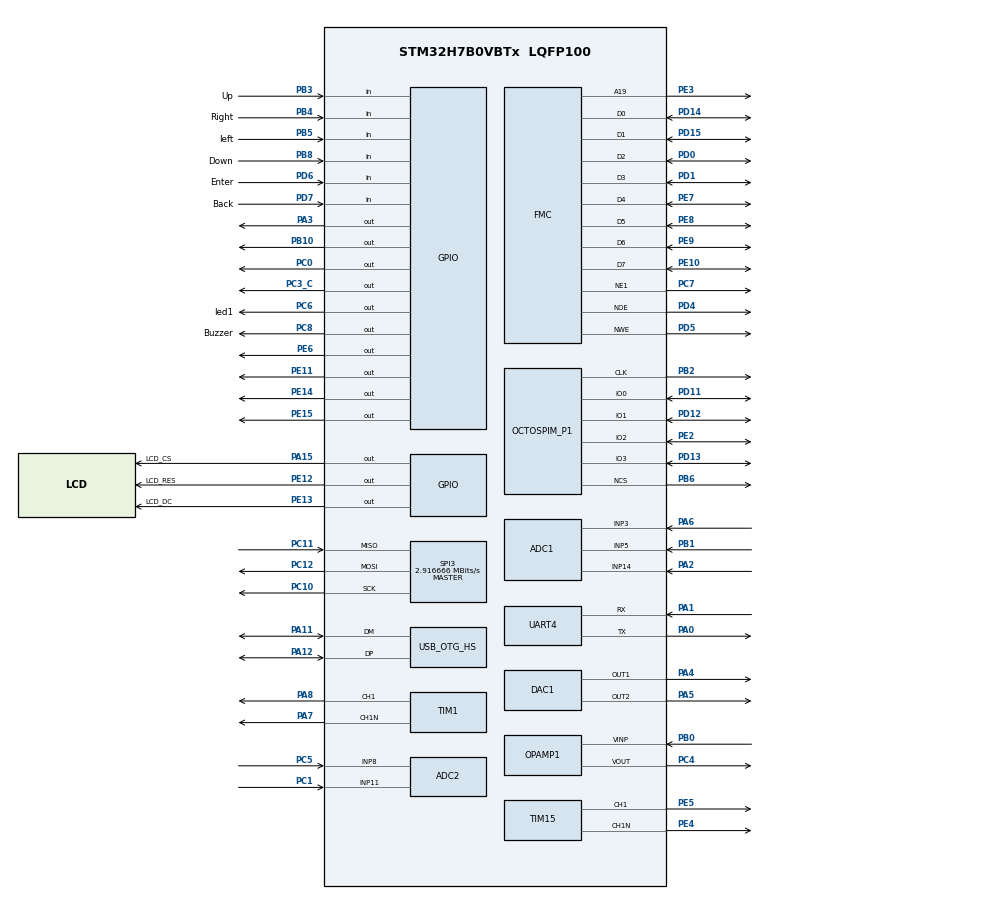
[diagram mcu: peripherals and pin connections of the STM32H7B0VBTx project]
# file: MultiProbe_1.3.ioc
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ADC1.Channel-0\#ChannelRegularConversion=ADC_CHANNEL_14
ADC1.ClockPrescaler=ADC_CLOCK_ASYNC_DIV2
ADC1.NbrOfConversionFlag=1
ADC1.OffsetNumber-0\#ChannelRegularConversion=ADC_OFFSET_NONE
ADC1.OffsetSignedSaturation-0\#ChannelRegularConversion=DISABLE
ADC1.Rank-0\#ChannelRegularConversion=1
ADC1.SamplingTime-0\#ChannelRegularConversion=ADC_SAMPLETIME_1CYCLE_5
ADC1.master=1
ADC2.Channel-0\#ChannelRegularConversion=ADC_CHANNEL_11
ADC2.ClockPrescaler=ADC_CLOCK_ASYNC_DIV2
ADC2.NbrOfConversionFlag=1
ADC2.OffsetNumber-0\#ChannelRegularConversion=ADC_OFFSET_NONE
ADC2.OffsetSignedSaturation-0\#ChannelRegularConversion=DISABLE
ADC2.Rank-0\#ChannelRegularConversion=1
ADC2.SamplingTime-0\#ChannelRegularConversion=ADC_SAMPLETIME_1CYCLE_5
DAC1.DAC_Channel-DAC_OUT1=DAC_CHANNEL_1
DAC1.DAC_Channel-DAC_OUT2=DAC_CHANNEL_2
Mcu.Family=STM32H7
Mcu.Name=STM32H7B0VBTx
Mcu.Package=LQFP100
NVIC.PriorityGroup=NVIC_PRIORITYGROUP_4
PA0.Mode=Asynchronous
PA0.Signal=UART4_TX
PA1.Mode=Asynchronous
PA1.Signal=UART4_RX
PA11.Mode=Device_Only_FS
PA11.Signal=USB_OTG_HS_DM
PA12.Mode=Device_Only_FS
PA12.Signal=USB_OTG_HS_DP
PA13.Mode=Serial_Wire
PA13.Signal=DEBUG_JTMS-SWDIO
PA14.Mode=Serial_Wire
PA14.Signal=DEBUG_JTCK-SWCLK
PA15.GPIO_Label=LCD_CS
PA15.PinState=GPIO_PIN_SET
PA15.Signal=GPIO_Output
PA2.Signal=ADCx_INP14
PA3.GPIO_PuPd=GPIO_PULLUP
PA3.PinState=GPIO_PIN_SET
PA3.Signal=GPIO_Output
PA4.Signal=COMP_DAC11_group
PA5.Signal=COMP_DAC12_group
PA6.Signal=ADCx_INP3
PA7.Mode=PWM Generation1 CH1 CH1N
PA7.Signal=TIM1_CH1N
PA8.Signal=S_TIM1_CH1
PB0.Mode=Follower
PB0.Signal=OPAMP1_VINP
PB1.Signal=ADCx_INP5
PB10.GPIO_PuPd=GPIO_PULLUP
PB10.PinState=GPIO_PIN_SET
PB10.Signal=GPIO_Output
PB12.Signal=SPI2_NSS
PB13.Signal=SPI2_SCK
PB2.Mode=O1_P1_CLK
PB2.Signal=OCTOSPIM_P1_CLK
PB3.GPIO_Label=Up
PB3.GPIO_PuPd=GPIO_PULLUP
PB3.Signal=GPIO_Input
PB4.GPIO_Label=Right
PB4.GPIO_PuPd=GPIO_PULLUP
PB4.Signal=GPIO_Input
PB5.GPIO_Label=left
PB5.GPIO_PuPd=GPIO_PULLUP
PB5.Signal=GPIO_Input
PB6.Mode=OCTOSPI1_Port1_NCS
PB6.Signal=OCTOSPIM_P1_NCS
PB8.GPIO_Label=Down
PB8.GPIO_PuPd=GPIO_PULLUP
PB8.Signal=GPIO_Input
PC0.GPIO_PuPd=GPIO_PULLUP
PC0.PinState=GPIO_PIN_SET
PC0.Signal=GPIO_Output
PC1.Signal=ADCx_INP11
PC10.Mode=Full_Duplex_Master
PC10.Signal=SPI3_SCK
PC11.Mode=Full_Duplex_Master
PC11.Signal=SPI3_MISO
PC12.Mode=Full_Duplex_Master
PC12.Signal=SPI3_MOSI
PC2_C.Signal=SPI2_MISO
PC3_C.GPIO_PuPd=GPIO_PULLUP
PC3_C.PinState=GPIO_PIN_SET
PC3_C.Signal=GPIO_Output
PC4.Mode=Follower
PC4.Signal=OPAMP1_VOUT
PC5.Signal=ADCx_INP8
PC6.GPIO_Label=led1
PC6.Signal=GPIO_Output
PC7.Mode=NorPsramChipSelect1_1
PC7.Signal=FMC_NE1
PC8.GPIO_Label=Buzzer
PC8.Signal=GPIO_Output
PD0.Signal=FMC_D2_DA2
PD1.Signal=FMC_D3_DA3
PD11.Mode=OCTOSPI1_IOL_Port1L
PD11.Signal=OCTOSPIM_P1_IO0
PD12.Mode=OCTOSPI1_IOL_Port1L
PD12.Signal=OCTOSPIM_P1_IO1
PD13.Mode=OCTOSPI1_IOL_Port1L
PD13.Signal=OCTOSPIM_P1_IO3
PD14.Signal=FMC_D0_DA0
PD15.Signal=FMC_D1_DA1
PD4.Signal=FMC_NOE
PD5.Signal=FMC_NWE
PD6.GPIO_Label=Enter
PD6.GPIO_PuPd=GPIO_PULLUP
PD6.Signal=GPIO_Input
PD7.GPIO_Label=Back
PD7.GPIO_PuPd=GPIO_PULLUP
PD7.Signal=GPIO_Input
PE10.Signal=FMC_D7_DA7
PE11.GPIO_PuPd=GPIO_PULLUP
PE11.PinState=GPIO_PIN_SET
PE11.Signal=GPIO_Output
PE12.GPIO_Label=LCD_RES
PE12.Signal=GPIO_Output
PE13.GPIO_Label=LCD_DC
PE13.Signal=GPIO_Output
PE14.GPIO_PuPd=GPIO_PULLUP
PE14.PinState=GPIO_PIN_SET
PE14.Signal=GPIO_Output
PE15.GPIO_PuPd=GPIO_PULLUP
PE15.PinState=GPIO_PIN_SET
PE15.Signal=GPIO_Output
PE2.Mode=OCTOSPI1_IOL_Port1L
PE2.Signal=OCTOSPIM_P1_IO2
PE3.Signal=FMC_A19
PE4.Mode=PWM Generation1 CH1 CH1N
PE4.Signal=TIM15_CH1N
PE5.Signal=S_TIM15_CH1
PE6.GPIO_ModeDefaultOutputPP=GPIO_MODE_OUTPUT_PP
PE6.GPIO_PuPd=GPIO_PULLUP
PE6.GPIO_Speed=GPIO_SPEED_FREQ_LOW
PE6.PinState=GPIO_PIN_SET
PE6.Signal=GPIO_Output
PE7.Signal=FMC_D4_DA4
PE8.Signal=FMC_D5_DA5
PE9.Signal=FMC_D6_DA6
PH0-OSC_IN.Mode=HSE-External-Oscillator
PH0-OSC_IN.Signal=RCC_OSC_IN
PH1-OSC_OUT.Mode=HSE-External-Oscillator
PH1-OSC_OUT.Signal=RCC_OSC_OUT
ProjectManager.HeapSize=0x200
ProjectManager.StackSize=0x400
ProjectManager.TargetToolchain=STM32CubeIDE
RCC.ADCFreq_Value=41666666.666666664
RCC.APB1Freq_Value=140000000
RCC.APB2Freq_Value=140000000
RCC.APB3Freq_Value=140000000
RCC.APB4Freq_Value=140000000
RCC.CDPPRE=RCC_APB3_DIV2
RCC.CDPPRE1=RCC_APB1_DIV2
RCC.CDPPRE2=RCC_APB2_DIV2
RCC.CortexFreq_Value=280000000
RCC.DIVM1=5
RCC.DIVM2=2
RCC.DIVN1=112
RCC.DIVN2=10
RCC.DIVP2=3
RCC.DIVQ1=12
RCC.HCLKFreq_Value=280000000
RCC.HSE_VALUE=25000000
RCC.PLL1_VCI_Range=RCC_PLL1VCIRANGE_3
RCC.PLL2FRACN=0
RCC.PLL2_VCI_Range=RCC_PLL2VCIRANGE_3
RCC.PLL3FRACN=0
RCC.PLLFRACN=0
RCC.SRDPPRE=RCC_APB4_DIV2
RCC.SYSCLKFreq_VALUE=280000000
RCC.SYSCLKSource=RCC_SYSCLKSOURCE_PLLCLK
RCC.USBFreq_Value=46666666.666666664
SH.ADCx_INP11.0=ADC2_INP11,IN11-Single-Ended
SH.ADCx_INP14.0=ADC1_INP14,IN14-Single-Ended
SH.ADCx_INP3.0=ADC1_INP3,IN3-Single-Ended
SH.ADCx_INP3.1=ADC2_INP3,IN3-Single-Ended
SH.ADCx_INP5.0=ADC1_INP5,IN5-Single-Ended
SH.ADCx_INP5.1=ADC2_INP5,IN5-Single-Ended
SH.ADCx_INP8.0=ADC2_INP8,IN8-Single-Ended
SH.COMP_DAC11_group.0=DAC1_OUT1,DAC_OUT1
SH.COMP_DAC12_group.0=DAC1_OUT2,DAC_OUT2
SH.FMC_A19.0=FMC_A19,A19_1
SH.FMC_D0_DA0.0=FMC_D0,8b-d1
SH.FMC_D1_DA1.0=FMC_D1,8b-d1
SH.FMC_D2_DA2.0=FMC_D2,8b-d1
SH.FMC_D3_DA3.0=FMC_D3,8b-d1
SH.FMC_D4_DA4.0=FMC_D4,8b-d1
SH.FMC_D5_DA5.0=FMC_D5,8b-d1
SH.FMC_D6_DA6.0=FMC_D6,8b-d1
SH.FMC_D7_DA7.0=FMC_D7,8b-d1
SH.FMC_NOE.0=FMC_NOE,Lcd1
SH.FMC_NWE.0=FMC_NWE,Lcd1
SH.S_TIM15_CH1.0=TIM15_CH1,PWM Generation1 CH1 CH1N
SH.S_TIM1_CH1.0=TIM1_CH1,PWM Generation1 CH1 CH1N
SPI3.BaudRatePrescaler=SPI_BAUDRATEPRESCALER_16
SPI3.CalculateBaudRate=2.916666 MBits/s
SPI3.DataSize=SPI_DATASIZE_8BIT
SPI3.Direction=SPI_DIRECTION_2LINES
SPI3.Mode=SPI_MODE_MASTER
SPI3.VirtualType=VM_MASTER
TIM1.Channel-PWM\ Generation1\ CH1\ CH1N=TIM_CHANNEL_1
TIM15.Channel-PWM\ Generation1\ CH1\ CH1N=TIM_CHANNEL_1
USB_OTG_HS.VirtualMode-Device_Only_FS=Device_Only_FS
VP_MEMORYMAP_VS_MEMORYMAP.Mode=CurAppReg
VP_OCTOSPI1_VS_octo.Mode=dual_quad_mode
VP_TIM15_VS_ClockSourceINT.Mode=Internal
VP_TIM1_VS_ClockSourceINT.Mode=Internal
board=custom

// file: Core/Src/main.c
/* USER CODE BEGIN Header */
/**
  ******************************************************************************
  * @file           : main.c
  * @brief          : Main program body
  ******************************************************************************
  * @attention
  *
  * Copyright (c) 2026 STMicroelectronics.
  * All rights reserved.
  *
  * This software is licensed under terms that can be found in the LICENSE file
  * in the root directory of this software component.
  * If no LICENSE file comes with this software, it is provided AS-IS.
  *
  ******************************************************************************
  */
/* USER CODE END Header */
#include "main.h"

/* USER CODE BEGIN Includes */
#include <stdio.h>
#include "lcd.h"
#include "leds.h"
#include "w25q64.h"
#include "image_store.h"
#include "video_player.h"
#include "adc_probe.h"
#include "statusbar.h"
#include "keypad.h"
#include "menu.h"
#include "app.h"
#include "carousel.h"
#include "probe_hw.h"
#include "device_lock.h"
/* USER CODE END Includes */

ADC_HandleTypeDef hadc1;
ADC_HandleTypeDef hadc2;

DAC_HandleTypeDef hdac1;

OSPI_HandleTypeDef hospi1;

OPAMP_HandleTypeDef hopamp1;

SPI_HandleTypeDef hspi3;

TIM_HandleTypeDef htim1;
TIM_HandleTypeDef htim15;

UART_HandleTypeDef huart4;

PCD_HandleTypeDef hpcd_USB_OTG_HS;

SRAM_HandleTypeDef hsram1;

/* USER CODE BEGIN PV */
/* Set to 1 to measure LCD frame rate (result in g_lcd_fps_x10 = FPS*10) */
#define LCD_FPS_BENCHMARK  0
volatile uint32_t g_lcd_fps_x10 = 0U;
volatile float g_vin, g_pb0, g_pc4, g_pb1, g_pa6, g_pa2, g_pc1;   // ← تعریف متغیرها اینجا
/* USER CODE END PV */

void SystemClock_Config(void);
void PeriphCommonClock_Config(void);
static void MX_GPIO_Init(void);
static void MX_ADC1_Init(void);
static void MX_ADC2_Init(void);
static void MX_DAC1_Init(void);
static void MX_FMC_Init(void);
static void MX_OCTOSPI1_Init(void);
static void MX_OPAMP1_Init(void);
static void MX_SPI3_Init(void);
static void MX_TIM1_Init(void);
static void MX_TIM15_Init(void);
static void MX_UART4_Init(void);
static void MX_USB_OTG_HS_PCD_Init(void);

/* USER CODE BEGIN 0 */
static void Beep(uint8_t count)
{
    for (uint8_t i = 0; i < count; i++) {
        HAL_GPIO_WritePin(GPIOC, GPIO_PIN_8, GPIO_PIN_SET);
        HAL_Delay(200);
        HAL_GPIO_WritePin(GPIOC, GPIO_PIN_8, GPIO_PIN_RESET);
        HAL_Delay(200);
    }
}
/* USER CODE END 0 */

int main(void)
{

  /* MCU Configuration--------------------------------------------------------*/

  /* Reset of all peripherals, Initializes the Flash interface and the Systick. */
  HAL_Init();

  /* USER CODE BEGIN Init */
  LCD_MPU_Config();
  /* USER CODE END Init */

  /* Configure the system clock */
  SystemClock_Config();

  /* Configure the peripherals common clocks */
  PeriphCommonClock_Config();

  /* Initialize all configured peripherals */
  MX_GPIO_Init();
  MX_ADC1_Init();
  MX_ADC2_Init();
  MX_DAC1_Init();
  MX_FMC_Init();
  /* QSPI flash is mapped + decrypted by Boot_ExternalInit() (xip_boot.c), called from SystemInit(). */
  MX_OPAMP1_Init();
  MX_SPI3_Init();
  MX_TIM1_Init();
  MX_TIM15_Init();
  MX_UART4_Init();
  MX_USB_OTG_HS_PCD_Init();
  /* USER CODE BEGIN 2 */
  Keypad_Init();
  StatusBar_Init();
  GPIO_InitTypeDef gi = {0};
  gi.Pin   = GPIO_PIN_8;
  gi.Mode  = GPIO_MODE_OUTPUT_PP;
  gi.Pull  = GPIO_NOPULL;
  gi.Speed = GPIO_SPEED_FREQ_LOW;
  HAL_GPIO_Init(GPIOC, &gi);

  LCD_Init();

  /* === قفل ضد-کپی بر پایه‌ی UID میکرو (device_lock.c) ===
   * اولین فلش: روی صفحه "NOT PROVISIONED" + 4 عدد هگز میاد؛ همونا رو توی device_lock.c
   * (DEVLOCK_EXPECTED0..3) بذار و دوباره فلش کن. از اون به بعد این فریمور فقط رو همین چیپ
   * بالا میاد -- روی یک میکروی دیگه (حتی با همین QSPI/فلش کپی‌شده) اینجا متوقف می‌مونه.
   * توجه: این به‌تنهایی کافی نیست؛ باید با Read-Out Protection (RDP) هم همراه بشه، وگرنه
   * کسی که از SWD فلش داخلی رو دامپ کنه هم رمز هم عدد مورد انتظار رو می‌بینه. */
  {
      uint32_t fp[4];
      DevLock_Result_t lr = DeviceLock_Check(fp);
      if (lr != DEVLOCK_OK)
      {
          LCD_FillColor(LCD_COLOR_BLACK);
          if (lr == DEVLOCK_UNPROVISIONED)
          {
              char line[32];
              LCD_DrawString(6, 50, "NOT PROVISIONED", LCD_COLOR_YELLOW, LCD_COLOR_BLACK, 1);
              LCD_DrawString(6, 70, "copy into", LCD_COLOR_WHITE, LCD_COLOR_BLACK, 1);
              LCD_DrawString(6, 82, "device_lock.c:", LCD_COLOR_WHITE, LCD_COLOR_BLACK, 1);
              for (uint8_t i = 0U; i < 4U; i++)
              {
                  snprintf(line, sizeof line, "FP%u 0x%08lX", (unsigned)i, (unsigned long)fp[i]);
                  LCD_DrawString(6, (uint16_t)(104 + i * 14), line, LCD_COLOR_CYAN, LCD_COLOR_BLACK, 1);
              }
          }
          else
          {
              LCD_DrawString(30, 100, "LOCKED", LCD_COLOR_RED, LCD_COLOR_BLACK, 3);
              LCD_DrawString(6, 150, "wrong chip / UID", LCD_COLOR_WHITE, LCD_COLOR_BLACK, 1);
          }
          for (;;) { HAL_Delay(1000); }   /* عمداً متوقف می‌مونه؛ بقیه‌ی main() هیچ‌وقت اجرا نمی‌شه */
      }
  }

  Adc_Init();
  Probe_Init();            /* همه‌ی OE ها HIGH (خاموش)، سوئیچ‌ها بیکار، PWM قطع */
  Adc_SelfTest();
  if (g_vdda > 3.0f && g_vdda < 3.6f) {
      Beep(1);      /* سالم */
  } else {
      Beep(3);      /* مشکل */
  }

  /* Make sure the logo is stored in IC1 (W25Q64), then show it from there.
   * Debug colors if something fails:
   *   YELLOW  = IC1 not detected (OSPI / wiring / ID != EF 40 17)
   *   MAGENTA = erase/program/verify of IC1 failed
   *   CYAN    = reading the image back from IC1 failed
   */
  LCD_FillColor(LCD_COLOR_RED);

  switch (Image_EnsureInFlash())
  {
  case IMG_OK_ALREADY:
  case IMG_OK_PROGRAMMED:
      if (LCD_LoadImageToRam() != HAL_OK || LCD_DrawImageFromRam() != HAL_OK)
      {
          LCD_FillColor(LCD_COLOR_CYAN);
          HAL_Delay(2500);
      }
      else
      {
          Video_Boot();    /* mailbox + پنجره‌ی کوتاه آپلود ویدیو از USB؛ بعدش برمی‌گرده */
          HAL_Delay(800);  /* لوگو یه لحظه دیده بشه */
      }
      break;
  default:
      HAL_Delay(2500);     /* رنگ خطا دیده بشه */
      break;
  }

  /* منوی اصلی */
  LCD_FillColor(LCD_COLOR_BLACK);
  StatusBar_Init();
  Carousel_Init();
  /* USER CODE END 2 */
#if LCD_FPS_BENCHMARK
  /* Redraws the cached image 100 times and stores the result in
   * g_lcd_fps_x10 (FPS * 10). Put a breakpoint on the while(1) below
   * and watch the variable in the debugger. */
  {
    CoreDebug->DEMCR |= CoreDebug_DEMCR_TRCENA_Msk;
    DWT->CYCCNT = 0U;
    DWT->CTRL  |= DWT_CTRL_CYCCNTENA_Msk;

    const uint32_t frames = 100U;
    uint32_t t0 = DWT->CYCCNT;
    for (uint32_t f = 0U; f < frames; f++)
    {
      (void)LCD_DrawImageFromRam();
    }
    uint32_t cycles = DWT->CYCCNT - t0;   /* fine for < ~10 s at 400 MHz */
    g_lcd_fps_x10 = (uint32_t)(((uint64_t)frames * SystemCoreClock * 10U) / cycles);
  }
#endif
  /* Infinite loop */
  while (1)
  {

    /* USER CODE BEGIN 3 */
    MenuInput_t in = Keypad_Poll();
    if (in != MENU_INPUT_NONE)
    {
      Carousel_HandleInput(in);   /* LEFT/RIGHT = صفحه‌ی بعد/قبل ، ENTER = ورود به صفحه */
    }
    StatusBar_Task();

    static uint32_t lastLed = 0U;
    if ((HAL_GetTick() - lastLed) >= 150U)
    {
      lastLed = HAL_GetTick();
      LEDs_UpdateVoltage(Adc_GetVin());
    }
    Carousel_Draw();
  }
  /* USER CODE END 3 */
}

void SystemClock_Config(void)
{
  RCC_OscInitTypeDef RCC_OscInitStruct = {0};
  RCC_ClkInitTypeDef RCC_ClkInitStruct = {0};

  /*AXI clock gating */
  RCC->CKGAENR = 0xFFFFFFFF;

  /** Supply configuration update enable
  */
  HAL_PWREx_ConfigSupply(PWR_LDO_SUPPLY);

  /** Configure the main internal regulator output voltage
  */
  __HAL_PWR_VOLTAGESCALING_CONFIG(PWR_REGULATOR_VOLTAGE_SCALE0);

  while(!__HAL_PWR_GET_FLAG(PWR_FLAG_VOSRDY)) {}

  /** Initializes the RCC Oscillators according to the specified parameters
  * in the RCC_OscInitTypeDef structure.
  */
  RCC_OscInitStruct.OscillatorType = RCC_OSCILLATORTYPE_LSI|RCC_OSCILLATORTYPE_HSE;
  RCC_OscInitStruct.HSEState = RCC_HSE_ON;
  RCC_OscInitStruct.LSIState = RCC_LSI_ON;
  RCC_OscInitStruct.PLL.PLLState = RCC_PLL_ON;
  RCC_OscInitStruct.PLL.PLLSource = RCC_PLLSOURCE_HSE;
  RCC_OscInitStruct.PLL.PLLM = 5;
  RCC_OscInitStruct.PLL.PLLN = 112;
  RCC_OscInitStruct.PLL.PLLP = 2;
  RCC_OscInitStruct.PLL.PLLQ = 12;
  RCC_OscInitStruct.PLL.PLLR = 2;
  RCC_OscInitStruct.PLL.PLLRGE = RCC_PLL1VCIRANGE_3;
  RCC_OscInitStruct.PLL.PLLVCOSEL = RCC_PLL1VCOWIDE;
  RCC_OscInitStruct.PLL.PLLFRACN = 0;
  if (HAL_RCC_OscConfig(&RCC_OscInitStruct) != HAL_OK)
  {
    Error_Handler();
  }

  /** Initializes the CPU, AHB and APB buses clocks
  */
  RCC_ClkInitStruct.ClockType = RCC_CLOCKTYPE_HCLK|RCC_CLOCKTYPE_SYSCLK
                              |RCC_CLOCKTYPE_PCLK1|RCC_CLOCKTYPE_PCLK2
                              |RCC_CLOCKTYPE_D3PCLK1|RCC_CLOCKTYPE_D1PCLK1;
  RCC_ClkInitStruct.SYSCLKSource = RCC_SYSCLKSOURCE_PLLCLK;
  RCC_ClkInitStruct.SYSCLKDivider = RCC_SYSCLK_DIV1;
  RCC_ClkInitStruct.AHBCLKDivider = RCC_HCLK_DIV1;
  RCC_ClkInitStruct.APB3CLKDivider = RCC_APB3_DIV2;
  RCC_ClkInitStruct.APB1CLKDivider = RCC_APB1_DIV2;
  RCC_ClkInitStruct.APB2CLKDivider = RCC_APB2_DIV2;
  RCC_ClkInitStruct.APB4CLKDivider = RCC_APB4_DIV2;

  if (HAL_RCC_ClockConfig(&RCC_ClkInitStruct, FLASH_LATENCY_6) != HAL_OK)
  {
    Error_Handler();
  }
}

void PeriphCommonClock_Config(void)
{
  RCC_PeriphCLKInitTypeDef PeriphClkInitStruct = {0};

  /** Initializes the peripherals clock
  */
  PeriphClkInitStruct.PeriphClockSelection = RCC_PERIPHCLK_ADC;
  PeriphClkInitStruct.PLL2.PLL2M = 2;
  PeriphClkInitStruct.PLL2.PLL2N = 10;
  PeriphClkInitStruct.PLL2.PLL2P = 3;
  PeriphClkInitStruct.PLL2.PLL2Q = 2;
  PeriphClkInitStruct.PLL2.PLL2R = 2;
  PeriphClkInitStruct.PLL2.PLL2RGE = RCC_PLL2VCIRANGE_3;
  PeriphClkInitStruct.PLL2.PLL2VCOSEL = RCC_PLL2VCOWIDE;
  PeriphClkInitStruct.PLL2.PLL2FRACN = 0;
  PeriphClkInitStruct.AdcClockSelection = RCC_ADCCLKSOURCE_PLL2;
  if (HAL_RCCEx_PeriphCLKConfig(&PeriphClkInitStruct) != HAL_OK)
  {
    Error_Handler();
  }
}

static void MX_ADC1_Init(void)
{

  ADC_MultiModeTypeDef multimode = {0};
  ADC_ChannelConfTypeDef sConfig = {0};

  /** Common config
  */
  hadc1.Instance = ADC1;
  hadc1.Init.ClockPrescaler = ADC_CLOCK_ASYNC_DIV2;
  hadc1.Init.Resolution = ADC_RESOLUTION_16B;
  hadc1.Init.ScanConvMode = ADC_SCAN_DISABLE;
  hadc1.Init.EOCSelection = ADC_EOC_SINGLE_CONV;
  hadc1.Init.LowPowerAutoWait = DISABLE;
  hadc1.Init.ContinuousConvMode = DISABLE;
  hadc1.Init.NbrOfConversion = 1;
  hadc1.Init.DiscontinuousConvMode = DISABLE;
  hadc1.Init.ExternalTrigConv = ADC_SOFTWARE_START;
  hadc1.Init.ExternalTrigConvEdge = ADC_EXTERNALTRIGCONVEDGE_NONE;
  hadc1.Init.ConversionDataManagement = ADC_CONVERSIONDATA_DR;
  hadc1.Init.Overrun = ADC_OVR_DATA_PRESERVED;
  hadc1.Init.LeftBitShift = ADC_LEFTBITSHIFT_NONE;
  hadc1.Init.OversamplingMode = DISABLE;
  if (HAL_ADC_Init(&hadc1) != HAL_OK)
  {
    Error_Handler();
  }

  /** Configure the ADC multi-mode
  */
  multimode.Mode = ADC_MODE_INDEPENDENT;
  if (HAL_ADCEx_MultiModeConfigChannel(&hadc1, &multimode) != HAL_OK)
  {
    Error_Handler();
  }

  /** Configure Regular Channel
  */
  sConfig.Channel = ADC_CHANNEL_14;
  sConfig.Rank = ADC_REGULAR_RANK_1;
  sConfig.SamplingTime = ADC_SAMPLETIME_1CYCLE_5;
  sConfig.SingleDiff = ADC_SINGLE_ENDED;
  sConfig.OffsetNumber = ADC_OFFSET_NONE;
  sConfig.Offset = 0;
  sConfig.OffsetSignedSaturation = DISABLE;
  if (HAL_ADC_ConfigChannel(&hadc1, &sConfig) != HAL_OK)
  {
    Error_Handler();
  }

}

static void MX_ADC2_Init(void)
{

  ADC_ChannelConfTypeDef sConfig = {0};

  /** Common config
  */
  hadc2.Instance = ADC2;
  hadc2.Init.ClockPrescaler = ADC_CLOCK_ASYNC_DIV2;
  hadc2.Init.Resolution = ADC_RESOLUTION_16B;
  hadc2.Init.ScanConvMode = ADC_SCAN_DISABLE;
  hadc2.Init.EOCSelection = ADC_EOC_SINGLE_CONV;
  hadc2.Init.LowPowerAutoWait = DISABLE;
  hadc2.Init.ContinuousConvMode = DISABLE;
  hadc2.Init.NbrOfConversion = 1;
  hadc2.Init.DiscontinuousConvMode = DISABLE;
  hadc2.Init.ExternalTrigConv = ADC_SOFTWARE_START;
  hadc2.Init.ExternalTrigConvEdge = ADC_EXTERNALTRIGCONVEDGE_NONE;
  hadc2.Init.ConversionDataManagement = ADC_CONVERSIONDATA_DR;
  hadc2.Init.Overrun = ADC_OVR_DATA_PRESERVED;
  hadc2.Init.LeftBitShift = ADC_LEFTBITSHIFT_NONE;
  hadc2.Init.OversamplingMode = DISABLE;
  if (HAL_ADC_Init(&hadc2) != HAL_OK)
  {
    Error_Handler();
  }

  /** Configure Regular Channel
  */
  sConfig.Channel = ADC_CHANNEL_11;
  sConfig.Rank = ADC_REGULAR_RANK_1;
  sConfig.SamplingTime = ADC_SAMPLETIME_1CYCLE_5;
  sConfig.SingleDiff = ADC_SINGLE_ENDED;
  sConfig.OffsetNumber = ADC_OFFSET_NONE;
  sConfig.Offset = 0;
  sConfig.OffsetSignedSaturation = DISABLE;
  if (HAL_ADC_ConfigChannel(&hadc2, &sConfig) != HAL_OK)
  {
    Error_Handler();
  }

}

static void MX_DAC1_Init(void)
{

  DAC_ChannelConfTypeDef sConfig = {0};

  /** DAC Initialization
  */
  hdac1.Instance = DAC1;
  if (HAL_DAC_Init(&hdac1) != HAL_OK)
  {
    Error_Handler();
  }

  /** DAC channel OUT1 config
  */
  sConfig.DAC_SampleAndHold = DAC_SAMPLEANDHOLD_DISABLE;
  sConfig.DAC_Trigger = DAC_TRIGGER_NONE;
  sConfig.DAC_OutputBuffer = DAC_OUTPUTBUFFER_ENABLE;
  sConfig.DAC_ConnectOnChipPeripheral = DAC_CHIPCONNECT_DISABLE;
  sConfig.DAC_UserTrimming = DAC_TRIMMING_FACTORY;
  if (HAL_DAC_ConfigChannel(&hdac1, &sConfig, DAC_CHANNEL_1) != HAL_OK)
  {
    Error_Handler();
  }

  /** DAC channel OUT2 config
  */
  if (HAL_DAC_ConfigChannel(&hdac1, &sConfig, DAC_CHANNEL_2) != HAL_OK)
  {
    Error_Handler();
  }

}

static void MX_OCTOSPI1_Init(void)
{

  OSPIM_CfgTypeDef sOspiManagerCfg = {0};

  /* OCTOSPI1 parameter configuration*/
  hospi1.Instance = OCTOSPI1;
  hospi1.Init.FifoThreshold = 1;
  hospi1.Init.DualQuad = HAL_OSPI_DUALQUAD_ENABLE;
  hospi1.Init.MemoryType = HAL_OSPI_MEMTYPE_MICRON;
  hospi1.Init.DeviceSize = 32;
  hospi1.Init.ChipSelectHighTime = 1;
  hospi1.Init.FreeRunningClock = HAL_OSPI_FREERUNCLK_DISABLE;
  hospi1.Init.ClockMode = HAL_OSPI_CLOCK_MODE_0;
  hospi1.Init.WrapSize = HAL_OSPI_WRAP_NOT_SUPPORTED;
  hospi1.Init.ClockPrescaler = 1;
  hospi1.Init.SampleShifting = HAL_OSPI_SAMPLE_SHIFTING_NONE;
  hospi1.Init.DelayHoldQuarterCycle = HAL_OSPI_DHQC_DISABLE;
  hospi1.Init.ChipSelectBoundary = 0;
  hospi1.Init.DelayBlockBypass = HAL_OSPI_DELAY_BLOCK_BYPASSED;
  hospi1.Init.MaxTran = 0;
  hospi1.Init.Refresh = 0;
  if (HAL_OSPI_Init(&hospi1) != HAL_OK)
  {
    Error_Handler();
  }
  sOspiManagerCfg.ClkPort = 1;
  sOspiManagerCfg.NCSPort = 1;
  sOspiManagerCfg.IOLowPort = HAL_OSPIM_IOPORT_1_LOW;
  if (HAL_OSPIM_Config(&hospi1, &sOspiManagerCfg, HAL_OSPI_TIMEOUT_DEFAULT_VALUE) != HAL_OK)
  {
    Error_Handler();
  }

}

static void MX_OPAMP1_Init(void)
{

  hopamp1.Instance = OPAMP1;
  hopamp1.Init.Mode = OPAMP_FOLLOWER_MODE;
  hopamp1.Init.NonInvertingInput = OPAMP_NONINVERTINGINPUT_IO0;
  hopamp1.Init.PowerMode = OPAMP_POWERMODE_NORMAL;
  hopamp1.Init.UserTrimming = OPAMP_TRIMMING_FACTORY;
  if (HAL_OPAMP_Init(&hopamp1) != HAL_OK)
  {
    Error_Handler();
  }

}

// static void MX_SPI2_Init(void)
//{
//
//  /* USER CODE BEGIN SPI2_Init 0 */
//
//  /* USER CODE END SPI2_Init 0 */
//
//  /* USER CODE BEGIN SPI2_Init 1 */
//
//  /* USER CODE END SPI2_Init 1 */
//  /* SPI2 parameter configuration*/
//  hspi2.Instance = SPI2;
//  hspi2.Init.Mode = SPI_MODE_MASTER;
//  hspi2.Init.Direction = SPI_DIRECTION_2LINES;
//  hspi2.Init.DataSize = SPI_DATASIZE_4BIT;
//  hspi2.Init.CLKPolarity = SPI_POLARITY_LOW;
//  hspi2.Init.CLKPhase = SPI_PHASE_1EDGE;
//  hspi2.Init.NSS = SPI_NSS_HARD_OUTPUT;
//  hspi2.Init.BaudRatePrescaler = SPI_BAUDRATEPRESCALER_2;
//  hspi2.Init.FirstBit = SPI_FIRSTBIT_MSB;
//  hspi2.Init.TIMode = SPI_TIMODE_DISABLE;
//  hspi2.Init.CRCCalculation = SPI_CRCCALCULATION_DISABLE;
//  hspi2.Init.CRCPolynomial = 0x0;
//  hspi2.Init.NSSPMode = SPI_NSS_PULSE_ENABLE;
//  hspi2.Init.NSSPolarity = SPI_NSS_POLARITY_LOW;
//  hspi2.Init.FifoThreshold = SPI_FIFO_THRESHOLD_01DATA;
//  hspi2.Init.TxCRCInitializationPattern = SPI_CRC_INITIALIZATION_ALL_ZERO_PATTERN;
//  hspi2.Init.RxCRCInitializationPattern = SPI_CRC_INITIALIZATION_ALL_ZERO_PATTERN;
//  hspi2.Init.MasterSSIdleness = SPI_MASTER_SS_IDLENESS_00CYCLE;
//  hspi2.Init.MasterInterDataIdleness = SPI_MASTER_INTERDATA_IDLENESS_00CYCLE;
//  hspi2.Init.MasterReceiverAutoSusp = SPI_MASTER_RX_AUTOSUSP_DISABLE;
//  hspi2.Init.MasterKeepIOState = SPI_MASTER_KEEP_IO_STATE_DISABLE;
//  hspi2.Init.IOSwap = SPI_IO_SWAP_DISABLE;
//  if (HAL_SPI_Init(&hspi2) != HAL_OK)
//  {
//    Error_Handler();
//  }
//  /* USER CODE BEGIN SPI2_Init 2 */
//
//  /* USER CODE END SPI2_Init 2 */
//
//}
static void MX_SPI3_Init(void)
{

  /* SPI3 parameter configuration*/
  hspi3.Instance = SPI3;
  hspi3.Init.Mode = SPI_MODE_MASTER;
  hspi3.Init.Direction = SPI_DIRECTION_2LINES;
  hspi3.Init.DataSize = SPI_DATASIZE_8BIT;
  hspi3.Init.CLKPolarity = SPI_POLARITY_LOW;
  hspi3.Init.CLKPhase = SPI_PHASE_1EDGE;
  hspi3.Init.NSS = SPI_NSS_SOFT;
  hspi3.Init.BaudRatePrescaler = SPI_BAUDRATEPRESCALER_16;
  hspi3.Init.FirstBit = SPI_FIRSTBIT_MSB;
  hspi3.Init.TIMode = SPI_TIMODE_DISABLE;
  hspi3.Init.CRCCalculation = SPI_CRCCALCULATION_DISABLE;
  hspi3.Init.CRCPolynomial = 0x0;
  hspi3.Init.NSSPMode = SPI_NSS_PULSE_ENABLE;
  hspi3.Init.NSSPolarity = SPI_NSS_POLARITY_LOW;
  hspi3.Init.FifoThreshold = SPI_FIFO_THRESHOLD_01DATA;
  hspi3.Init.TxCRCInitializationPattern = SPI_CRC_INITIALIZATION_ALL_ZERO_PATTERN;
  hspi3.Init.RxCRCInitializationPattern = SPI_CRC_INITIALIZATION_ALL_ZERO_PATTERN;
  hspi3.Init.MasterSSIdleness = SPI_MASTER_SS_IDLENESS_00CYCLE;
  hspi3.Init.MasterInterDataIdleness = SPI_MASTER_INTERDATA_IDLENESS_00CYCLE;
  hspi3.Init.MasterReceiverAutoSusp = SPI_MASTER_RX_AUTOSUSP_DISABLE;
  hspi3.Init.MasterKeepIOState = SPI_MASTER_KEEP_IO_STATE_DISABLE;
  hspi3.Init.IOSwap = SPI_IO_SWAP_DISABLE;
  if (HAL_SPI_Init(&hspi3) != HAL_OK)
  {
    Error_Handler();
  }

}

static void MX_TIM1_Init(void)
{

  TIM_ClockConfigTypeDef sClockSourceConfig = {0};
  TIM_MasterConfigTypeDef sMasterConfig = {0};
  TIM_OC_InitTypeDef sConfigOC = {0};
  TIM_BreakDeadTimeConfigTypeDef sBreakDeadTimeConfig = {0};

  htim1.Instance = TIM1;
  htim1.Init.Prescaler = 0;
  htim1.Init.CounterMode = TIM_COUNTERMODE_UP;
  htim1.Init.Period = 65535;
  htim1.Init.ClockDivision = TIM_CLOCKDIVISION_DIV1;
  htim1.Init.RepetitionCounter = 0;
  htim1.Init.AutoReloadPreload = TIM_AUTORELOAD_PRELOAD_DISABLE;
  if (HAL_TIM_Base_Init(&htim1) != HAL_OK)
  {
    Error_Handler();
  }
  sClockSourceConfig.ClockSource = TIM_CLOCKSOURCE_INTERNAL;
  if (HAL_TIM_ConfigClockSource(&htim1, &sClockSourceConfig) != HAL_OK)
  {
    Error_Handler();
  }
  if (HAL_TIM_PWM_Init(&htim1) != HAL_OK)
  {
    Error_Handler();
  }
  sMasterConfig.MasterOutputTrigger = TIM_TRGO_RESET;
  sMasterConfig.MasterOutputTrigger2 = TIM_TRGO2_RESET;
  sMasterConfig.MasterSlaveMode = TIM_MASTERSLAVEMODE_DISABLE;
  if (HAL_TIMEx_MasterConfigSynchronization(&htim1, &sMasterConfig) != HAL_OK)
  {
    Error_Handler();
  }
  sConfigOC.OCMode = TIM_OCMODE_PWM1;
  sConfigOC.Pulse = 0;
  sConfigOC.OCPolarity = TIM_OCPOLARITY_HIGH;
  sConfigOC.OCNPolarity = TIM_OCNPOLARITY_HIGH;
  sConfigOC.OCFastMode = TIM_OCFAST_DISABLE;
  sConfigOC.OCIdleState = TIM_OCIDLESTATE_RESET;
  sConfigOC.OCNIdleState = TIM_OCNIDLESTATE_RESET;
  if (HAL_TIM_PWM_ConfigChannel(&htim1, &sConfigOC, TIM_CHANNEL_1) != HAL_OK)
  {
    Error_Handler();
  }
  sBreakDeadTimeConfig.OffStateRunMode = TIM_OSSR_DISABLE;
  sBreakDeadTimeConfig.OffStateIDLEMode = TIM_OSSI_DISABLE;
  sBreakDeadTimeConfig.LockLevel = TIM_LOCKLEVEL_OFF;
  sBreakDeadTimeConfig.DeadTime = 0;
  sBreakDeadTimeConfig.BreakState = TIM_BREAK_DISABLE;
  sBreakDeadTimeConfig.BreakPolarity = TIM_BREAKPOLARITY_HIGH;
  sBreakDeadTimeConfig.BreakFilter = 0;
  sBreakDeadTimeConfig.Break2State = TIM_BREAK2_DISABLE;
  sBreakDeadTimeConfig.Break2Polarity = TIM_BREAK2POLARITY_HIGH;
  sBreakDeadTimeConfig.Break2Filter = 0;
  sBreakDeadTimeConfig.AutomaticOutput = TIM_AUTOMATICOUTPUT_DISABLE;
  if (HAL_TIMEx_ConfigBreakDeadTime(&htim1, &sBreakDeadTimeConfig) != HAL_OK)
  {
    Error_Handler();
  }
  HAL_TIM_MspPostInit(&htim1);

}

static void MX_TIM15_Init(void)
{

  TIM_ClockConfigTypeDef sClockSourceConfig = {0};
  TIM_MasterConfigTypeDef sMasterConfig = {0};
  TIM_OC_InitTypeDef sConfigOC = {0};
  TIM_BreakDeadTimeConfigTypeDef sBreakDeadTimeConfig = {0};

  htim15.Instance = TIM15;
  htim15.Init.Prescaler = 0;
  htim15.Init.CounterMode = TIM_COUNTERMODE_UP;
  htim15.Init.Period = 65535;
  htim15.Init.ClockDivision = TIM_CLOCKDIVISION_DIV1;
  htim15.Init.RepetitionCounter = 0;
  htim15.Init.AutoReloadPreload = TIM_AUTORELOAD_PRELOAD_DISABLE;
  if (HAL_TIM_Base_Init(&htim15) != HAL_OK)
  {
    Error_Handler();
  }
  sClockSourceConfig.ClockSource = TIM_CLOCKSOURCE_INTERNAL;
  if (HAL_TIM_ConfigClockSource(&htim15, &sClockSourceConfig) != HAL_OK)
  {
    Error_Handler();
  }
  if (HAL_TIM_PWM_Init(&htim15) != HAL_OK)
  {
    Error_Handler();
  }
  sMasterConfig.MasterOutputTrigger = TIM_TRGO_RESET;
  sMasterConfig.MasterSlaveMode = TIM_MASTERSLAVEMODE_DISABLE;
  if (HAL_TIMEx_MasterConfigSynchronization(&htim15, &sMasterConfig) != HAL_OK)
  {
    Error_Handler();
  }
  sConfigOC.OCMode = TIM_OCMODE_PWM1;
  sConfigOC.Pulse = 0;
  sConfigOC.OCPolarity = TIM_OCPOLARITY_HIGH;
  sConfigOC.OCNPolarity = TIM_OCNPOLARITY_HIGH;
  sConfigOC.OCFastMode = TIM_OCFAST_DISABLE;
  sConfigOC.OCIdleState = TIM_OCIDLESTATE_RESET;
  sConfigOC.OCNIdleState = TIM_OCNIDLESTATE_RESET;
  if (HAL_TIM_PWM_ConfigChannel(&htim15, &sConfigOC, TIM_CHANNEL_1) != HAL_OK)
  {
    Error_Handler();
  }
  sBreakDeadTimeConfig.OffStateRunMode = TIM_OSSR_DISABLE;
  sBreakDeadTimeConfig.OffStateIDLEMode = TIM_OSSI_DISABLE;
  sBreakDeadTimeConfig.LockLevel = TIM_LOCKLEVEL_OFF;
  sBreakDeadTimeConfig.DeadTime = 0;
  sBreakDeadTimeConfig.BreakState = TIM_BREAK_DISABLE;
  sBreakDeadTimeConfig.BreakPolarity = TIM_BREAKPOLARITY_HIGH;
  sBreakDeadTimeConfig.BreakFilter = 0;
  sBreakDeadTimeConfig.AutomaticOutput = TIM_AUTOMATICOUTPUT_DISABLE;
  if (HAL_TIMEx_ConfigBreakDeadTime(&htim15, &sBreakDeadTimeConfig) != HAL_OK)
  {
    Error_Handler();
  }
  HAL_TIM_MspPostInit(&htim15);

}

static void MX_UART4_Init(void)
{

  huart4.Instance = UART4;
  huart4.Init.BaudRate = 115200;
  huart4.Init.WordLength = UART_WORDLENGTH_8B;
  huart4.Init.StopBits = UART_STOPBITS_1;
  huart4.Init.Parity = UART_PARITY_NONE;
  huart4.Init.Mode = UART_MODE_TX_RX;
  huart4.Init.HwFlowCtl = UART_HWCONTROL_NONE;
  huart4.Init.OverSampling = UART_OVERSAMPLING_16;
  huart4.Init.OneBitSampling = UART_ONE_BIT_SAMPLE_DISABLE;
  huart4.Init.ClockPrescaler = UART_PRESCALER_DIV1;
  huart4.AdvancedInit.AdvFeatureInit = UART_ADVFEATURE_NO_INIT;
  if (HAL_UART_Init(&huart4) != HAL_OK)
  {
    Error_Handler();
  }
  if (HAL_UARTEx_SetTxFifoThreshold(&huart4, UART_TXFIFO_THRESHOLD_1_8) != HAL_OK)
  {
    Error_Handler();
  }
  if (HAL_UARTEx_SetRxFifoThreshold(&huart4, UART_RXFIFO_THRESHOLD_1_8) != HAL_OK)
  {
    Error_Handler();
  }
  if (HAL_UARTEx_DisableFifoMode(&huart4) != HAL_OK)
  {
    Error_Handler();
  }

}

static void MX_USB_OTG_HS_PCD_Init(void)
{

  hpcd_USB_OTG_HS.Instance = USB_OTG_HS;
  hpcd_USB_OTG_HS.Init.dev_endpoints = 9;
  hpcd_USB_OTG_HS.Init.speed = PCD_SPEED_FULL;
  hpcd_USB_OTG_HS.Init.dma_enable = DISABLE;
  hpcd_USB_OTG_HS.Init.phy_itface = USB_OTG_EMBEDDED_PHY;
  hpcd_USB_OTG_HS.Init.Sof_enable = DISABLE;
  hpcd_USB_OTG_HS.Init.low_power_enable = DISABLE;
  hpcd_USB_OTG_HS.Init.lpm_enable = DISABLE;
  hpcd_USB_OTG_HS.Init.vbus_sensing_enable = DISABLE;
  hpcd_USB_OTG_HS.Init.use_dedicated_ep1 = DISABLE;
  hpcd_USB_OTG_HS.Init.use_external_vbus = DISABLE;
  if (HAL_PCD_Init(&hpcd_USB_OTG_HS) != HAL_OK)
  {
    Error_Handler();
  }

}

/* FMC initialization function */
static void MX_FMC_Init(void)
{

  FMC_NORSRAM_TimingTypeDef Timing = {0};

  /** Perform the SRAM1 memory initialization sequence
  */
  hsram1.Instance = FMC_NORSRAM_DEVICE;
  hsram1.Extended = FMC_NORSRAM_EXTENDED_DEVICE;
  /* hsram1.Init */
  hsram1.Init.NSBank = FMC_NORSRAM_BANK1;
  hsram1.Init.DataAddressMux = FMC_DATA_ADDRESS_MUX_DISABLE;
  hsram1.Init.MemoryType = FMC_MEMORY_TYPE_SRAM;
  hsram1.Init.MemoryDataWidth = FMC_NORSRAM_MEM_BUS_WIDTH_8;
  hsram1.Init.BurstAccessMode = FMC_BURST_ACCESS_MODE_DISABLE;
  hsram1.Init.WaitSignalPolarity = FMC_WAIT_SIGNAL_POLARITY_LOW;
  hsram1.Init.WaitSignalActive = FMC_WAIT_TIMING_BEFORE_WS;
  hsram1.Init.WriteOperation = FMC_WRITE_OPERATION_ENABLE;
  hsram1.Init.WaitSignal = FMC_WAIT_SIGNAL_DISABLE;
  hsram1.Init.ExtendedMode = FMC_EXTENDED_MODE_DISABLE;
  hsram1.Init.AsynchronousWait = FMC_ASYNCHRONOUS_WAIT_DISABLE;
  hsram1.Init.WriteBurst = FMC_WRITE_BURST_DISABLE;
  hsram1.Init.ContinuousClock = FMC_CONTINUOUS_CLOCK_SYNC_ONLY;
  hsram1.Init.WriteFifo = FMC_WRITE_FIFO_ENABLE;
  hsram1.Init.PageSize = FMC_PAGE_SIZE_NONE;
  /* Timing */
  Timing.AddressSetupTime = 15;
  Timing.AddressHoldTime = 15;
  Timing.DataSetupTime = 255;
  Timing.BusTurnAroundDuration = 15;
  Timing.CLKDivision = 16;
  Timing.DataLatency = 17;
  Timing.AccessMode = FMC_ACCESS_MODE_A;
  /* ExtTiming */

  if (HAL_SRAM_Init(&hsram1, &Timing, NULL) != HAL_OK)
  {
    Error_Handler( );
  }

  /* USER CODE BEGIN FMC_Init 2 */
  /* 8-bit LCD: FIFO must stay disabled (re-applied in LCD_BusSetup). */
  /* USER CODE END FMC_Init 2 */
}

static void MX_GPIO_Init(void)
{
  GPIO_InitTypeDef GPIO_InitStruct = {0};

  /* GPIO Ports Clock Enable */
  __HAL_RCC_GPIOE_CLK_ENABLE();
  __HAL_RCC_GPIOH_CLK_ENABLE();
  __HAL_RCC_GPIOC_CLK_ENABLE();
  __HAL_RCC_GPIOA_CLK_ENABLE();
  __HAL_RCC_GPIOB_CLK_ENABLE();
  __HAL_RCC_GPIOD_CLK_ENABLE();

  /* Set all LEDs OFF at startup */
  HAL_GPIO_WritePin(GPIOC, GPIO_PIN_6, GPIO_PIN_RESET);
  HAL_GPIO_WritePin(GPIOD,
                    GPIO_PIN_8 | GPIO_PIN_9 | GPIO_PIN_10,
                    GPIO_PIN_RESET);

  /* Configure Yellow LED: PC6 */
  GPIO_InitStruct.Pin = GPIO_PIN_6;
  GPIO_InitStruct.Mode = GPIO_MODE_OUTPUT_PP;
  GPIO_InitStruct.Pull = GPIO_NOPULL;
  GPIO_InitStruct.Speed = GPIO_SPEED_FREQ_LOW;
  HAL_GPIO_Init(GPIOC, &GPIO_InitStruct);

  /* Configure Red, Blue and Green LEDs: PD8, PD9, PD10 */
  GPIO_InitStruct.Pin = GPIO_PIN_8 | GPIO_PIN_9 | GPIO_PIN_10;
  GPIO_InitStruct.Mode = GPIO_MODE_OUTPUT_PP;
  GPIO_InitStruct.Pull = GPIO_NOPULL;
  GPIO_InitStruct.Speed = GPIO_SPEED_FREQ_LOW;
  HAL_GPIO_Init(GPIOD, &GPIO_InitStruct);
  /*Configure GPIO pin Output Level */
  HAL_GPIO_WritePin(GPIOE, GPIO_PIN_6|GPIO_PIN_11|GPIO_PIN_14|GPIO_PIN_15, GPIO_PIN_SET);

  /*Configure GPIO pin Output Level */
  HAL_GPIO_WritePin(GPIOC, GPIO_PIN_0|GPIO_PIN_3, GPIO_PIN_SET);

  /*Configure GPIO pin Output Level */
  HAL_GPIO_WritePin(GPIOA, GPIO_PIN_3|LCD_CS_Pin, GPIO_PIN_SET);

  /*Configure GPIO pin Output Level */
  HAL_GPIO_WritePin(GPIOE, LCD_RES_Pin|LCD_DC_Pin, GPIO_PIN_RESET);

  /*Configure GPIO pin Output Level */
  HAL_GPIO_WritePin(GPIOB, GPIO_PIN_10, GPIO_PIN_SET);

  /*Configure GPIO pin Output Level */
  HAL_GPIO_WritePin(GPIOC, led1_Pin|Buzzer_Pin, GPIO_PIN_RESET);

  /*Configure GPIO pins : PE6 PE11 PE14 PE15 */
  GPIO_InitStruct.Pin = GPIO_PIN_6|GPIO_PIN_11|GPIO_PIN_14|GPIO_PIN_15;
  GPIO_InitStruct.Mode = GPIO_MODE_OUTPUT_PP;
  GPIO_InitStruct.Pull = GPIO_PULLUP;
  GPIO_InitStruct.Speed = GPIO_SPEED_FREQ_LOW;
  HAL_GPIO_Init(GPIOE, &GPIO_InitStruct);

  /*Configure GPIO pins : PC0 PC3 */
  GPIO_InitStruct.Pin = GPIO_PIN_0|GPIO_PIN_3;
  GPIO_InitStruct.Mode = GPIO_MODE_OUTPUT_PP;
  GPIO_InitStruct.Pull = GPIO_PULLUP;
  GPIO_InitStruct.Speed = GPIO_SPEED_FREQ_LOW;
  HAL_GPIO_Init(GPIOC, &GPIO_InitStruct);

  /*Configure GPIO pin : PC2 */
  GPIO_InitStruct.Pin = GPIO_PIN_2;
  GPIO_InitStruct.Mode = GPIO_MODE_AF_PP;
  GPIO_InitStruct.Pull = GPIO_NOPULL;
  GPIO_InitStruct.Speed = GPIO_SPEED_FREQ_LOW;
  GPIO_InitStruct.Alternate = GPIO_AF5_SPI2;
  HAL_GPIO_Init(GPIOC, &GPIO_InitStruct);

  /*Configure GPIO pin : PA3 */
  GPIO_InitStruct.Pin = GPIO_PIN_3;
  GPIO_InitStruct.Mode = GPIO_MODE_OUTPUT_PP;
  GPIO_InitStruct.Pull = GPIO_PULLUP;
  GPIO_InitStruct.Speed = GPIO_SPEED_FREQ_LOW;
  HAL_GPIO_Init(GPIOA, &GPIO_InitStruct);

  /*Configure GPIO pins : LCD_RES_Pin LCD_DC_Pin */
  GPIO_InitStruct.Pin = LCD_RES_Pin|LCD_DC_Pin;
  GPIO_InitStruct.Mode = GPIO_MODE_OUTPUT_PP;
  GPIO_InitStruct.Pull = GPIO_NOPULL;
  GPIO_InitStruct.Speed = GPIO_SPEED_FREQ_LOW;
  HAL_GPIO_Init(GPIOE, &GPIO_InitStruct);

  /*Configure GPIO pin : PB10 */
  GPIO_InitStruct.Pin = GPIO_PIN_10;
  GPIO_InitStruct.Mode = GPIO_MODE_OUTPUT_PP;
  GPIO_InitStruct.Pull = GPIO_PULLUP;
  GPIO_InitStruct.Speed = GPIO_SPEED_FREQ_LOW;
  HAL_GPIO_Init(GPIOB, &GPIO_InitStruct);

  /*Configure GPIO pins : PB12 PB13 */
  GPIO_InitStruct.Pin = GPIO_PIN_12|GPIO_PIN_13;
  GPIO_InitStruct.Mode = GPIO_MODE_AF_PP;
  GPIO_InitStruct.Pull = GPIO_NOPULL;
  GPIO_InitStruct.Speed = GPIO_SPEED_FREQ_LOW;
  GPIO_InitStruct.Alternate = GPIO_AF5_SPI2;
  HAL_GPIO_Init(GPIOB, &GPIO_InitStruct);

  /*Configure GPIO pins : led1_Pin Buzzer_Pin */
  GPIO_InitStruct.Pin = led1_Pin|Buzzer_Pin;
  GPIO_InitStruct.Mode = GPIO_MODE_OUTPUT_PP;
  GPIO_InitStruct.Pull = GPIO_NOPULL;
  GPIO_InitStruct.Speed = GPIO_SPEED_FREQ_LOW;
  HAL_GPIO_Init(GPIOC, &GPIO_InitStruct);

  /*Configure GPIO pin : LCD_CS_Pin */
  GPIO_InitStruct.Pin = LCD_CS_Pin;
  GPIO_InitStruct.Mode = GPIO_MODE_OUTPUT_PP;
  GPIO_InitStruct.Pull = GPIO_NOPULL;
  GPIO_InitStruct.Speed = GPIO_SPEED_FREQ_LOW;
  HAL_GPIO_Init(LCD_CS_GPIO_Port, &GPIO_InitStruct);

  /*Configure GPIO pins : Enter_Pin Back_Pin */
  GPIO_InitStruct.Pin = Enter_Pin|Back_Pin;
  GPIO_InitStruct.Mode = GPIO_MODE_INPUT;
  GPIO_InitStruct.Pull = GPIO_PULLUP;
  HAL_GPIO_Init(GPIOD, &GPIO_InitStruct);

  /*Configure GPIO pins : Up_Pin Right_Pin left_Pin Down_Pin */
  GPIO_InitStruct.Pin = Up_Pin|Right_Pin|left_Pin|Down_Pin;
  GPIO_InitStruct.Mode = GPIO_MODE_INPUT;
  GPIO_InitStruct.Pull = GPIO_PULLUP;
  HAL_GPIO_Init(GPIOB, &GPIO_InitStruct);

  /*AnalogSwitch Config */
  HAL_SYSCFG_AnalogSwitchConfig(SYSCFG_SWITCH_PC3, SYSCFG_SWITCH_PC3_CLOSE);

}

void Error_Handler(void)
{
  /* USER CODE BEGIN Error_Handler_Debug */
  /* User can add his own implementation to report the HAL error return state */
  __disable_irq();
  while (1)
  {
	  HAL_GPIO_TogglePin(led1_GPIO_Port, led1_Pin);

	      for (volatile uint32_t i = 0; i < 2000000; i++)
	      {
	        __NOP();
	      }
  }
  /* USER CODE END Error_Handler_Debug */
}
